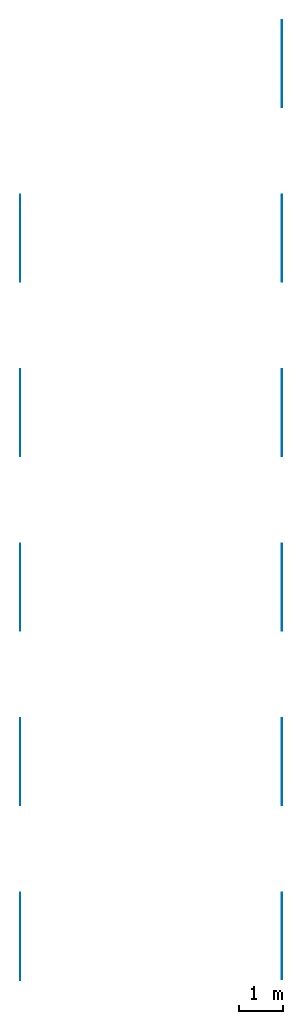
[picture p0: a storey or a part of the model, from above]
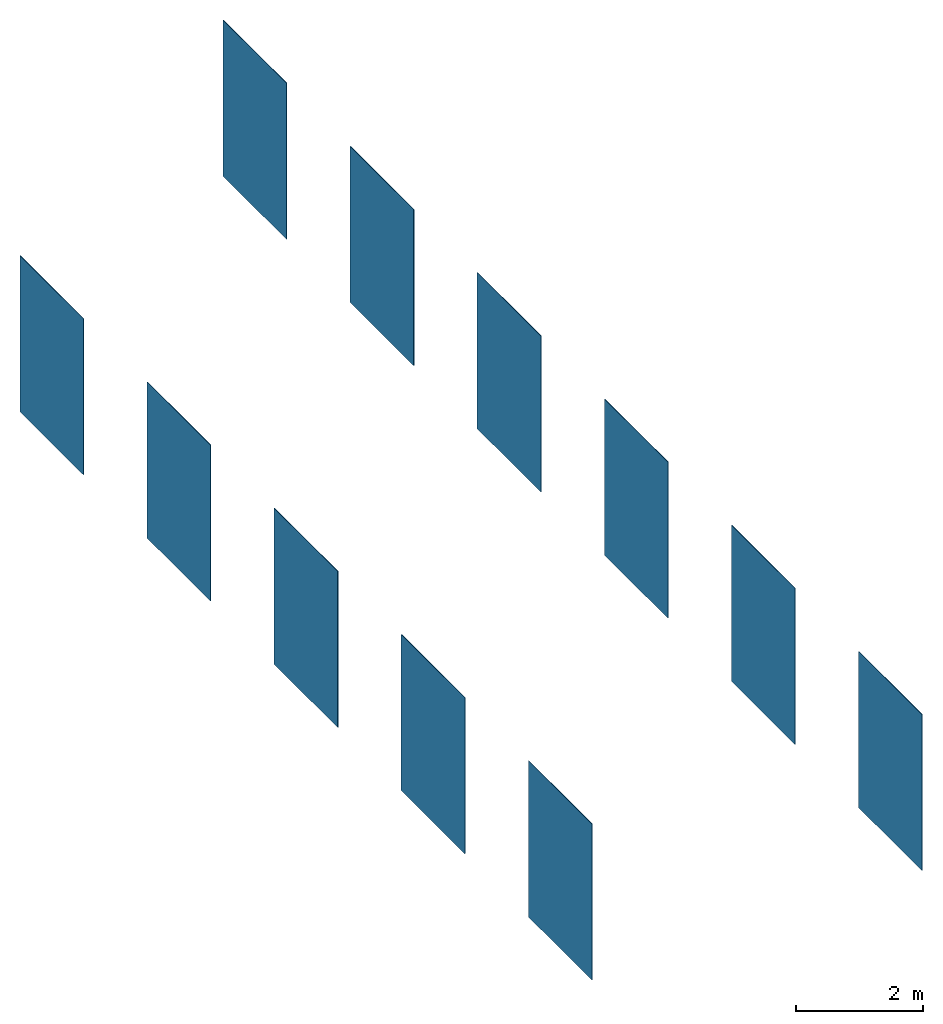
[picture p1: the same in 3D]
Properties of the parts of a building model (IFC2X3)

# File
Description: ViewDefinition [CoordinationView_V2.0]
File name: Project Number
Time: 2019-04-24T18:58:20
Written by: The EXPRESS Data Manager Version 5.02.0100.07 : 28 Aug 2013
Made in: 20181011_1645(x64) - Exporter 17.2.0.0 - Alternate UI 17.2.0.0
Comment: STEP Physical File produced by: The EXPRESS Data Manager Version 5.02.0100.07 : 28 Aug 2013 * Module: EDMstepFileFactory/EDMstandAlone * Creation date: Wed Apr 24 18:58:20 2019 * Host: aiepmoliner * Database: C:\Users\ES0050~1\AppData\Local\Temp\{C89440D0-0C4B-4D37-A4ED-84024C0F3F08}\ifc * Database version: 5507 * Database creation date: Wed Apr 24 18:58:17 2019 * Schema: IFC2X3 * Model: DataRepository.ifc * Model creation date: Wed Apr 24 18:58:18 2019 * Header model: DataRepository.ifc_HeaderModel * Header model creation date: Wed Apr 24 18:58:18 2019 * EDMuser: sdai-user * EDMgroup: sdai-group * License ID and type: 5605 : Permanent license. Expiry date: * EDMstepFileFactory options: 020000

# IfcProject, Project Number
LongName: Project Name; Phase: Project Status

# IfcSite, Default
RefLatitude: 42, 21, 31, 181945; RefLongitude: -71, -3, -24, -263305; RefElevation: 0 mm

# IfcBuildingStorey, Level 1
LongName: Level 1; Elevation: 0 mm

# IfcWallStandardCase: Basic Wall:PGR_AnticColonial_CeramicTiles_Nazari_Asilah-115x115mm-100213765, Basic Wall:PGR_AnticColonial_CeramicTiles_Nazari_Asilah-115x115mm-100213765:211309
In: Level 1
Type - PredefinedType: STANDARD; Material: PGR_AnticColonial_CeramicTiles_Nazari_Asilah-115x115mm-100213765 11 mm
Type - NBS_General - Author: Porcelanosa Group; BIMObjectName: PGR_AnticColonial_CeramicTiles_Nazari_Asilah-115x115mm-100213765; ManufacturerURL: anticcolonial.com; NBSDescription: Ceramic Tiles; NBSReference: 45-80-95/310; ProductInformation: http://calidad.info-grupo.com:8081/GeneraFicha3/PDF?articulo=100213765&lang=EN&un=0; Revision: n/a; Uniclass2015Code: Pr_35_93_96_19; Uniclass2015Title: Ceramic Tiles; Uniclass2015Version: Products v1.5; Version: 1
Type - COBie - AccessibilityPerformance: See ProductInformation (Technical PDF); AssetType: Fixed; Category: Pr_35_93_96_19:Ceramic Tiles; CodePerformance: ISO-13006:2012; UNE-EN 14411:2012; Color: n/a; Constituents: Clays, feldespat and glaze; Description: NAZARI series from ANTIC COLONIAL, 12.5x12.5 cm (11 mm thickness) and according to UNE-EN 14411; DurationUnit: year; ExpectedLife: 50; Features: See ProductInformation (Technical PDF); Grade: First quality; Manufacturer: bim.gp@porcelanosagrupo.com; ModelNumber: 100213765; ModelReference: Nazari Asilah 11.5x11.5x1-1.1 cm; Name: CeramicTiles_Nazari_Asilah-115x115mm-100213765; ReplacementCost: n/a; Shape: Squared; Size: 115x115x11 mm; Sustainability Performance: See ProductInformation (Technical PDF); WarrantyDescription: Manufacturer warranty, applicable worldwide, with the pertinent national legislation prevailing in all cases and covering at least a 3-year period; all products must have been manufactured and fitted in accordance with the Fabricator's Manual, and have been used and cared for in accordance with the Guide to Use, Cleaning and Care available on the web page www.porcelanosa.com; WarrantyDurationLabor: n/a; WarrantyDurationParts: 3; WarrantyDurationUnit: year; WarrantyGuarantorLabor: n/a; WarrantyGuarantorParts: bim.gp@porcelanosagrupo.com
Type - Pset_CoveringCommon - IsExternal: no; Reference: n/a; AcousticRating: n/a; Finish: Tone Variations, Gloss, Relief; FireRating: A1; FlammabilityRating: Class 0; FragilityRating: n/a; Material: Ceramic; SurfaceSpreadOfFlame: Class 0; ThermalTransmittance: 209.091 kg/K/s3; TotalThickness: 11 mm
Type - IFC - IfcExportAS: IfcCovering; IfcExportType: CLADDING
Type - NBS_Data - HasSurfaceRoughness: yes; AbrasionResistance: 1: Wall Tiles; BreakingStrength: n/a; ChemicalResistance: Class 'A' for swimming pools and cleaning products (resists attack); minimum Class 'B' for acids and bases; Collection: Ceramica Tradicional; CreationDate: 2019/04; Dcof: n/a; FlexuralStrength: n/a; FrostResistance: n/a; Group: N/A; MoistureExpansion: <0.1 mm/m; RampTest: n/a; RecycledContent: n/a; Series: Nazari; SlipResistanceValuePendulumTestValue: n/a; StainResistance: Class 5: Easy cleaning with water; SurfaceQuality: Without surface defects; ThermalShockResistance: Conforms to ISO 10545–12; UpecC: n/a; UpecE: n/a; UpecP: n/a; UpecU: n/a; WaterAbsorption: n/a
COBie - AssetIdentifier: n/a; BarCode: n/a; InstallationDate: 1900-12-31T23:59:59; TagNumber: n/a; WarrantyStartDate: 1900-12-31T23:59:59

# IfcWallStandardCase: Basic Wall:PGR_AnticColonial_CeramicTiles_Nazari_Casablanca_Brillo-115x115mm-100243592, Basic Wall:PGR_AnticColonial_CeramicTiles_Nazari_Casablanca_Brillo-115x115mm-100243592:211308
In: Level 1
Type - PredefinedType: STANDARD; Material: PGR_AnticColonial_CeramicTiles_Nazari_Casablanca_Brillo-115x115mm-100243592 11 mm
Type - NBS_General - Author: Porcelanosa Group; BIMObjectName: PGR_AnticColonial_CeramicTiles_Nazari_Casablanca_Brillo-115x115mm-100243592; ManufacturerURL: anticcolonial.com; NBSDescription: Ceramic Tiles; NBSReference: 45-80-95/310; ProductInformation: http://calidad.info-grupo.com:8081/GeneraFicha3/PDF?articulo=100243592&lang=EN&un=0; Revision: n/a; Uniclass2015Code: Pr_35_93_96_19; Uniclass2015Title: Ceramic Tiles; Uniclass2015Version: Products v1.5; Version: 1
Type - COBie - AccessibilityPerformance: See ProductInformation (Technical PDF); AssetType: Fixed; Category: Walls; CodePerformance: ISO-13006:2012; UNE-EN 14411:2012; Color: n/a; Constituents: Clays, feldespat and glaze; Description: NAZARI series from ANTIC COLONIAL, 11.5x11.5 cm (11 mm thickness) and according to UNE-EN 14411; DurationUnit: year; ExpectedLife: 50; Features: See ProductInformation (Technical PDF); Grade: First quality; Manufacturer: bim.gp@porcelanosagrupo.com; ModelNumber: 100243592; ModelReference: Nazari Casablanca Brillo 11.5x11.5x1-1.1 cm; Name: CeramicTiles_Nazari_Casablanca_Brillo-115x115mm-100243592; ReplacementCost: n/a; Shape: Squared; Size: 115x115x11 mm; Sustainability Performance: See ProductInformation (Technical PDF); WarrantyDescription: Manufacturer warranty, applicable worldwide, with the pertinent national legislation prevailing in all cases and covering at least a 3-year period; all products must have been manufactured and fitted in accordance with the Fabricator's Manual, and have been used and cared for in accordance with the Guide to Use, Cleaning and Care available on the web page www.porcelanosa.com; WarrantyDurationLabor: n/a; WarrantyDurationParts: 3; WarrantyDurationUnit: year; WarrantyGuarantorLabor: n/a; WarrantyGuarantorParts: bim.gp@porcelanosagrupo.com
Type - Pset_CoveringCommon - IsExternal: no; Reference: n/a; AcousticRating: n/a; Finish: Tone Variations, Gloss, Relief; FireRating: A1; FlammabilityRating: Class 0; FragilityRating: n/a; Material: Ceramic; SurfaceSpreadOfFlame: Class 0; ThermalTransmittance: 209.091 kg/K/s3; TotalThickness: 11 mm
Type - IFC - IfcExportAS: IfcCovering; IfcExportType: CLADDING
Type - NBS_Data - HasSurfaceRoughness: yes; AbrasionResistance: 1: Wall Tiles; BreakingStrength: n/a; ChemicalResistance: Class 'A' for swimming pools and cleaning products (resists attack); minimum Class 'B' for acids and bases; Collection: Ceramica Tradicional; CreationDate: 2019/04; Dcof: n/a; FlexuralStrength: n/a; FrostResistance: n/a; Group: N/A; MoistureExpansion: <0.1 mm/m; RampTest: n/a; RecycledContent: n/a; Series: Nazari; SlipResistanceValuePendulumTestValue: n/a; StainResistance: Class 5: Easy cleaning with water; SurfaceQuality: Without surface defects; ThermalShockResistance: Conforms to ISO 10545–12; UpecC: n/a; UpecE: n/a; UpecP: n/a; UpecU: n/a; WaterAbsorption: n/a
COBie - AssetIdentifier: n/a; BarCode: n/a; InstallationDate: 1900-12-31T23:59:59; TagNumber: n/a; WarrantyStartDate: 1900-12-31T23:59:59

# IfcWallStandardCase: Basic Wall:PGR_AnticColonial_CeramicTiles_Nazari_Casablanca_Mate-115x115mm-100243581, Basic Wall:PGR_AnticColonial_CeramicTiles_Nazari_Casablanca_Mate-115x115mm-100243581:211307
In: Level 1
Type - PredefinedType: STANDARD; Material: PGR_AnticColonial_CeramicTiles_Nazari_Casablanca_Mate-115x115mm-100243581 11 mm
Type - NBS_General - Author: Porcelanosa Group; BIMObjectName: PGR_AnticColonial_CeramicTiles_Nazari_Casablanca_Mate-115x115mm-100243581; ManufacturerURL: anticcolonial.com; NBSDescription: Ceramic Tiles; NBSReference: 45-80-95/310; ProductInformation: http://calidad.info-grupo.com:8081/GeneraFicha3/PDF?articulo=100243581&lang=EN&un=0; Revision: n/a; Uniclass2015Code: Pr_35_93_96_19; Uniclass2015Title: Ceramic Tiles; Uniclass2015Version: Products v1.5; Version: 1
Type - COBie - AccessibilityPerformance: See ProductInformation (Technical PDF); AssetType: Fixed; Category: Walls; CodePerformance: ISO-13006:2012; UNE-EN 14411:2012; Color: n/a; Constituents: Clays, feldespat and glaze; Description: NAZARI series from ANTIC COLONIAL, 11.5x11.5 cm (11 mm thickness) and according to UNE-EN 14411; DurationUnit: year; ExpectedLife: 50; Features: See ProductInformation (Technical PDF); Grade: First quality; Manufacturer: bim.gp@porcelanosagrupo.com; ModelNumber: 100243581; ModelReference: Nazari Casablanca Mate 11.5x11.5x1-1.1 cm; Name: CeramicTiles_Nazari_Casablanca_Mate-115x115mm-100243581; ReplacementCost: n/a; Shape: Squared; Size: 115x115x11 mm; Sustainability Performance: See ProductInformation (Technical PDF); WarrantyDescription: Manufacturer warranty, applicable worldwide, with the pertinent national legislation prevailing in all cases and covering at least a 3-year period; all products must have been manufactured and fitted in accordance with the Fabricator's Manual, and have been used and cared for in accordance with the Guide to Use, Cleaning and Care available on the web page www.porcelanosa.com; WarrantyDurationLabor: n/a; WarrantyDurationParts: 3; WarrantyDurationUnit: year; WarrantyGuarantorLabor: n/a; WarrantyGuarantorParts: bim.gp@porcelanosagrupo.com
Type - Pset_CoveringCommon - IsExternal: no; Reference: n/a; AcousticRating: n/a; Finish: Tone Variations, Matte, Relief; FireRating: A1; FlammabilityRating: Class 0; FragilityRating: n/a; Material: Ceramic; SurfaceSpreadOfFlame: Class 0; ThermalTransmittance: 209.091 kg/K/s3; TotalThickness: 11 mm
Type - IFC - IfcExportAS: IfcCovering; IfcExportType: CLADDING
Type - NBS_Data - HasSurfaceRoughness: yes; AbrasionResistance: 1: Wall Tiles; BreakingStrength: n/a; ChemicalResistance: Class 'A' for swimming pools and cleaning products (resists attack); minimum Class 'B' for acids and bases; Collection: Ceramica Tradicional; CreationDate: 2019/04; Dcof: n/a; FlexuralStrength: n/a; FrostResistance: n/a; Group: N/A; MoistureExpansion: <0.1 mm/m; RampTest: n/a; RecycledContent: n/a; Series: Nazari; SlipResistanceValuePendulumTestValue: n/a; StainResistance: Class 5: Easy cleaning with water; SurfaceQuality: Without surface defects; ThermalShockResistance: Conforms to ISO 10545–12; UpecC: n/a; UpecE: n/a; UpecP: n/a; UpecU: n/a; WaterAbsorption: n/a
COBie - AssetIdentifier: n/a; BarCode: n/a; InstallationDate: 1900-12-31T23:59:59; TagNumber: n/a; WarrantyStartDate: 1900-12-31T23:59:59

# IfcWallStandardCase: Basic Wall:PGR_AnticColonial_CeramicTiles_Nazari_Chauen-115x115mm-100213777, Basic Wall:PGR_AnticColonial_CeramicTiles_Nazari_Chauen-115x115mm-100213777:211306
In: Level 1
Type - PredefinedType: STANDARD; Material: PGR_AnticColonial_CeramicTiles_Nazari_Chauen-115x115mm-100213777 11 mm
Type - NBS_General - Author: Porcelanosa Group; BIMObjectName: PGR_AnticColonial_CeramicTiles_Nazari_Chauen-115x115mm-100213777; ManufacturerURL: anticcolonial.com; NBSDescription: Ceramic Tiles; NBSReference: 45-80-95/310; ProductInformation: http://calidad.info-grupo.com:8081/GeneraFicha3/PDF?articulo=100213777&lang=EN&un=0; Revision: n/a; Uniclass2015Code: Pr_35_93_96_19; Uniclass2015Title: Ceramic Tiles; Uniclass2015Version: Products v1.5; Version: 1
Type - COBie - AccessibilityPerformance: See ProductInformation (Technical PDF); AssetType: Fixed; Category: Pr_35_93_96_19:Ceramic Tiles; CodePerformance: ISO-13006:2012; UNE-EN 14411:2012; Color: n/a; Constituents: Clays, feldespat and glaze; Description: NAZARI series from ANTIC COLONIAL, 12.5x12.5 cm (11 mm thickness) and according to UNE-EN 14411; DurationUnit: year; ExpectedLife: 50; Features: See ProductInformation (Technical PDF); Grade: First quality; Manufacturer: bim.gp@porcelanosagrupo.com; ModelNumber: 100213777; ModelReference: Nazari Chauen 11.5x11.5x1-1.1 cm; Name: CeramicTiles_Nazari_Chauen-115x115mm-100213777; ReplacementCost: n/a; Shape: Squared; Size: 115x115x11 mm; Sustainability Performance: See ProductInformation (Technical PDF); WarrantyDescription: Manufacturer warranty, applicable worldwide, with the pertinent national legislation prevailing in all cases and covering at least a 3-year period; all products must have been manufactured and fitted in accordance with the Fabricator's Manual, and have been used and cared for in accordance with the Guide to Use, Cleaning and Care available on the web page www.porcelanosa.com; WarrantyDurationLabor: n/a; WarrantyDurationParts: 3; WarrantyDurationUnit: year; WarrantyGuarantorLabor: n/a; WarrantyGuarantorParts: bim.gp@porcelanosagrupo.com
Type - Pset_CoveringCommon - IsExternal: no; Reference: n/a; AcousticRating: n/a; Finish: Tone Variations, Gloss, Relief; FireRating: A1; FlammabilityRating: Class 0; FragilityRating: n/a; Material: Ceramic; SurfaceSpreadOfFlame: Class 0; ThermalTransmittance: 209.091 kg/K/s3; TotalThickness: 11 mm
Type - IFC - IfcExportAS: IfcCovering; IfcExportType: CLADDING
Type - NBS_Data - HasSurfaceRoughness: yes; AbrasionResistance: 1: Wall Tiles; BreakingStrength: n/a; ChemicalResistance: Class 'A' for swimming pools and cleaning products (resists attack); minimum Class 'B' for acids and bases; Collection: Ceramica Tradicional; CreationDate: 2019/04; Dcof: n/a; FlexuralStrength: n/a; FrostResistance: n/a; Group: N/A; MoistureExpansion: <0.1 mm/m; RampTest: n/a; RecycledContent: n/a; Series: Nazari; SlipResistanceValuePendulumTestValue: n/a; StainResistance: Class 5: Easy cleaning with water; SurfaceQuality: Without surface defects; ThermalShockResistance: Conforms to ISO 10545–12; UpecC: n/a; UpecE: n/a; UpecP: n/a; UpecU: n/a; WaterAbsorption: n/a
COBie - AssetIdentifier: n/a; BarCode: n/a; InstallationDate: 1900-12-31T23:59:59; TagNumber: n/a; WarrantyStartDate: 1900-12-31T23:59:59

# IfcWallStandardCase: Basic Wall:PGR_AnticColonial_CeramicTiles_Nazari_Fes-115x115mm-100213766, Basic Wall:PGR_AnticColonial_CeramicTiles_Nazari_Fes-115x115mm-100213766:211305
In: Level 1
Type - PredefinedType: STANDARD; Material: PGR_AnticColonial_CeramicTiles_Nazari_Fes-115x115mm-100213766 11 mm
Type - NBS_General - Author: Porcelanosa Group; BIMObjectName: PGR_AnticColonial_CeramicTiles_Nazari_Fes-115x115mm-100213766; ManufacturerURL: anticcolonial.com; NBSDescription: Ceramic Tiles; NBSReference: 45-80-95/310; ProductInformation: http://calidad.info-grupo.com:8081/GeneraFicha3/PDF?articulo=100213766&lang=EN&un=0; Revision: n/a; Uniclass2015Code: Pr_35_93_96_19; Uniclass2015Title: Ceramic Tiles; Uniclass2015Version: Products v1.5; Version: 1
Type - COBie - AccessibilityPerformance: See ProductInformation (Technical PDF); AssetType: Fixed; Category: Walls; CodePerformance: ISO-13006:2012; UNE-EN 14411:2012; Color: n/a; Constituents: Clays, feldespat and glaze; Description: NAZARI series from ANTIC COLONIAL, 12.5x12.5 cm (11 mm thickness) and according to UNE-EN 14411; DurationUnit: year; ExpectedLife: 50; Features: See ProductInformation (Technical PDF); Grade: First quality; Manufacturer: bim.gp@porcelanosagrupo.com; ModelNumber: 100213766; ModelReference: Nazari Fes 11.5x11.5x1-1.1 cm; Name: CeramicTiles_Nazari_Fes-115x115mm-100213766; ReplacementCost: n/a; Shape: Squared; Size: 115x115x11 mm; Sustainability Performance: See ProductInformation (Technical PDF); WarrantyDescription: Manufacturer warranty, applicable worldwide, with the pertinent national legislation prevailing in all cases and covering at least a 3-year period; all products must have been manufactured and fitted in accordance with the Fabricator's Manual, and have been used and cared for in accordance with the Guide to Use, Cleaning and Care available on the web page www.porcelanosa.com; WarrantyDurationLabor: n/a; WarrantyDurationParts: 3; WarrantyDurationUnit: year; WarrantyGuarantorLabor: n/a; WarrantyGuarantorParts: bim.gp@porcelanosagrupo.com
Type - Pset_CoveringCommon - IsExternal: no; Reference: n/a; AcousticRating: n/a; Finish: Tone Variations, Gloss, Relief; FireRating: A1; FlammabilityRating: Class 0; FragilityRating: n/a; Material: Ceramic; SurfaceSpreadOfFlame: Class 0; ThermalTransmittance: 209.091 kg/K/s3; TotalThickness: 11 mm
Type - IFC - IfcExportAS: IfcCovering; IfcExportType: CLADDING
Type - NBS_Data - HasSurfaceRoughness: yes; AbrasionResistance: 1: Wall Tiles; BreakingStrength: n/a; ChemicalResistance: Class 'A' for swimming pools and cleaning products (resists attack); minimum Class 'B' for acids and bases; Collection: Ceramica Tradicional; CreationDate: 2019/04; Dcof: n/a; FlexuralStrength: n/a; FrostResistance: n/a; Group: N/A; MoistureExpansion: <0.1 mm/m; RampTest: n/a; RecycledContent: n/a; Series: Nazari; SlipResistanceValuePendulumTestValue: n/a; StainResistance: Class 5: Easy cleaning with water; SurfaceQuality: Without surface defects; ThermalShockResistance: Conforms to ISO 10545–12; UpecC: n/a; UpecE: n/a; UpecP: n/a; UpecU: n/a; WaterAbsorption: n/a
COBie - AssetIdentifier: n/a; BarCode: n/a; InstallationDate: 1900-12-31T23:59:59; TagNumber: n/a; WarrantyStartDate: 1900-12-31T23:59:59

# IfcWallStandardCase: Basic Wall:PGR_AnticColonial_CeramicTiles_Nazari_Ifrane-115x115mm-100213784, Basic Wall:PGR_AnticColonial_CeramicTiles_Nazari_Ifrane-115x115mm-100213784:211304
In: Level 1
Type - PredefinedType: STANDARD; Material: PGR_AnticColonial_CeramicTiles_Nazari_Ifrane-115x115mm-100213784 11 mm
Type - NBS_General - Author: Porcelanosa Group; BIMObjectName: PGR_AnticColonial_CeramicTiles_Nazari_Ifrane-115x115mm-100213784; ManufacturerURL: anticcolonial.com; NBSDescription: Ceramic Tiles; NBSReference: 45-80-95/310; ProductInformation: http://calidad.info-grupo.com:8081/GeneraFicha3/PDF?articulo=100213784&lang=EN&un=0; Revision: n/a; Uniclass2015Code: Pr_35_93_96_19; Uniclass2015Title: Ceramic Tiles; Uniclass2015Version: Products v1.5; Version: 1
Type - COBie - AccessibilityPerformance: See ProductInformation (Technical PDF); AssetType: Fixed; Category: Pr_35_93_96_19:Ceramic Tiles; CodePerformance: ISO-13006:2012; UNE-EN 14411:2012; Color: n/a; Constituents: Clays, feldespat and glaze; Description: NAZARI series from ANTIC COLONIAL, 12.5x12.5 cm (11 mm thickness) and according to UNE-EN 14411; DurationUnit: year; ExpectedLife: 50; Features: See ProductInformation (Technical PDF); Grade: First quality; Manufacturer: bim.gp@porcelanosagrupo.com; ModelNumber: 100213784; ModelReference: Nazari Ifrane 11.5x11.5x1-1.1 cm; Name: CeramicTiles_Nazari_Ifrane-115x115mm-100213784; ReplacementCost: n/a; Shape: Squared; Size: 115x115x11 mm; Sustainability Performance: See ProductInformation (Technical PDF); WarrantyDescription: Manufacturer warranty, applicable worldwide, with the pertinent national legislation prevailing in all cases and covering at least a 3-year period; all products must have been manufactured and fitted in accordance with the Fabricator's Manual, and have been used and cared for in accordance with the Guide to Use, Cleaning and Care available on the web page www.porcelanosa.com; WarrantyDurationLabor: n/a; WarrantyDurationParts: 3; WarrantyDurationUnit: year; WarrantyGuarantorLabor: n/a; WarrantyGuarantorParts: bim.gp@porcelanosagrupo.com
Type - Pset_CoveringCommon - AcousticRating: n/a; Finish: Tone Variations, Gloss, Relief; FireRating: A1; FlammabilityRating: Class 0; FragilityRating: n/a; IsExternal: no; Material: Ceramic; SurfaceSpreadOfFlame: Class 0; ThermalTransmittance: 209.091 kg/K/s3; TotalThickness: 11 mm; Reference: n/a
Type - IFC - IfcExportAS: IfcCovering; IfcExportType: CLADDING
Type - NBS_Data - AbrasionResistance: 1: Wall Tiles; BreakingStrength: n/a; ChemicalResistance: Class 'A' for swimming pools and cleaning products (resists attack); minimum Class 'B' for acids and bases; Collection: Ceramica Tradicional; CreationDate: 2019/04; Dcof: n/a; FlexuralStrength: n/a; FrostResistance: n/a; Group: N/A; HasSurfaceRoughness: yes; MoistureExpansion: <0.1 mm/m; RampTest: n/a; RecycledContent: n/a; Series: Nazari; SlipResistanceValuePendulumTestValue: n/a; StainResistance: Class 5: Easy cleaning with water; SurfaceQuality: Without surface defects; ThermalShockResistance: Conforms to ISO 10545–12; UpecC: n/a; UpecE: n/a; UpecP: n/a; UpecU: n/a; WaterAbsorption: n/a
COBie - AssetIdentifier: n/a; BarCode: n/a; InstallationDate: 1900-12-31T23:59:59; TagNumber: n/a; WarrantyStartDate: 1900-12-31T23:59:59

# IfcWallStandardCase: Basic Wall:PGR_AnticColonial_CeramicTiles_Nazari_Marrakech-115x115mm-100213785, Basic Wall:PGR_AnticColonial_CeramicTiles_Nazari_Marrakech-115x115mm-100213785:213014
In: Level 1
Type - PredefinedType: STANDARD; Material: PGR_AnticColonial_CeramicTiles_Nazari_Marrakech-115x115mm-100213785 11 mm
Type - NBS_General - Author: Porcelanosa Group; BIMObjectName: PGR_AnticColonial_CeramicTiles_Nazari_Marrakech-115x115mm-100213785; ManufacturerURL: anticcolonial.com; NBSDescription: Ceramic Tiles; NBSReference: 45-80-95/310; ProductInformation: http://calidad.info-grupo.com:8081/GeneraFicha3/PDF?articulo=100213785&lang=EN&un=0; Revision: n/a; Uniclass2015Code: Pr_35_93_96_19; Uniclass2015Title: Ceramic Tiles; Uniclass2015Version: Products v1.5; Version: 1
Type - COBie - AccessibilityPerformance: See ProductInformation (Technical PDF); AssetType: Fixed; Category: Pr_35_93_96_19:Ceramic Tiles; CodePerformance: ISO-13006:2012; UNE-EN 14411:2012; Color: n/a; Constituents: Clays, feldespat and glaze; Description: NAZARI series from ANTIC COLONIAL, 12.5x12.5 cm (11 mm thickness) and according to UNE-EN 14411; DurationUnit: year; ExpectedLife: 50; Features: See ProductInformation (Technical PDF); Grade: First quality; Manufacturer: bim.gp@porcelanosagrupo.com; ModelNumber: 100213785; ModelReference: Nazari Marrakech 11.5x11.5x1-1.1 cm; Name: CeramicTiles_Nazari_Marrakech-115x115mm-100213785; ReplacementCost: n/a; Shape: Squared; Size: 115x115x11 mm; Sustainability Performance: See ProductInformation (Technical PDF); WarrantyDescription: Manufacturer warranty, applicable worldwide, with the pertinent national legislation prevailing in all cases and covering at least a 3-year period; all products must have been manufactured and fitted in accordance with the Fabricator's Manual, and have been used and cared for in accordance with the Guide to Use, Cleaning and Care available on the web page www.porcelanosa.com; WarrantyDurationLabor: n/a; WarrantyDurationParts: 3; WarrantyDurationUnit: year; WarrantyGuarantorLabor: n/a; WarrantyGuarantorParts: bim.gp@porcelanosagrupo.com
Type - Pset_CoveringCommon - IsExternal: no; Reference: n/a; AcousticRating: n/a; Finish: Tone Variations, Gloss, Relief; FireRating: A1; FlammabilityRating: Class 0; FragilityRating: n/a; Material: Ceramic; SurfaceSpreadOfFlame: Class 0; ThermalTransmittance: 209.091 kg/K/s3; TotalThickness: 11 mm
Type - IFC - IfcExportAS: IfcCovering; IfcExportType: CLADDING
Type - NBS_Data - HasSurfaceRoughness: yes; AbrasionResistance: 1: Wall Tiles; BreakingStrength: n/a; ChemicalResistance: Class 'A' for swimming pools and cleaning products (resists attack); minimum Class 'B' for acids and bases; Collection: Ceramica Tradicional; CreationDate: 2019/04; Dcof: n/a; FlexuralStrength: n/a; FrostResistance: n/a; Group: N/A; MoistureExpansion: <0.1 mm/m; RampTest: n/a; RecycledContent: n/a; Series: Nazari; SlipResistanceValuePendulumTestValue: n/a; StainResistance: Class 5: Easy cleaning with water; SurfaceQuality: Without surface defects; ThermalShockResistance: Conforms to ISO 10545–12; UpecC: n/a; UpecE: n/a; UpecP: n/a; UpecU: n/a; WaterAbsorption: n/a
COBie - AssetIdentifier: n/a; BarCode: n/a; InstallationDate: 1900-12-31T23:59:59; TagNumber: n/a; WarrantyStartDate: 1900-12-31T23:59:59

# IfcWallStandardCase: Basic Wall:PGR_AnticColonial_CeramicTiles_Nazari_Rabat-115x115mm-100243567, Basic Wall:PGR_AnticColonial_CeramicTiles_Nazari_Rabat-115x115mm-100243567:213013
In: Level 1
Type - PredefinedType: STANDARD; Material: PGR_AnticColonial_CeramicTiles_Nazari_Rabat-115x115mm-100243567 11 mm
Type - NBS_General - Author: Porcelanosa Group; BIMObjectName: PGR_AnticColonial_CeramicTiles_Nazari_Rabat-115x115mm-100243567; ManufacturerURL: anticcolonial.com; NBSDescription: Ceramic Tiles; NBSReference: 45-80-95/310; ProductInformation: http://calidad.info-grupo.com:8081/GeneraFicha3/PDF?articulo=100243567&lang=EN&un=0; Revision: n/a; Uniclass2015Code: Pr_35_93_96_19; Uniclass2015Title: Ceramic Tiles; Uniclass2015Version: Products v1.5; Version: 1
Type - COBie - AccessibilityPerformance: See ProductInformation (Technical PDF); AssetType: Fixed; Category: Pr_35_93_96_19:Ceramic Tiles; CodePerformance: ISO-13006:2012; UNE-EN 14411:2012; Color: n/a; Constituents: Clays, feldespat and glaze; Description: NAZARI series from ANTIC COLONIAL, 11.5x11.5 cm (11 mm thickness) and according to UNE-EN 14411; DurationUnit: year; ExpectedLife: 50; Features: See ProductInformation (Technical PDF); Grade: First quality; Manufacturer: bim.gp@porcelanosagrupo.com; ModelNumber: 100243567; ModelReference: Nazari Rabat 11.5x11.5x1-1.1 cm; Name: CeramicTiles_Nazari_Rabat-115x115mm-100243567; ReplacementCost: n/a; Shape: Squared; Size: 115x115x11 mm; Sustainability Performance: See ProductInformation (Technical PDF); WarrantyDescription: Manufacturer warranty, applicable worldwide, with the pertinent national legislation prevailing in all cases and covering at least a 3-year period; all products must have been manufactured and fitted in accordance with the Fabricator's Manual, and have been used and cared for in accordance with the Guide to Use, Cleaning and Care available on the web page www.porcelanosa.com; WarrantyDurationLabor: n/a; WarrantyDurationParts: 3; WarrantyDurationUnit: year; WarrantyGuarantorLabor: n/a; WarrantyGuarantorParts: bim.gp@porcelanosagrupo.com
Type - Pset_CoveringCommon - IsExternal: no; Reference: n/a; AcousticRating: n/a; Finish: Tone Variations, Gloss, Relief; FireRating: A1; FlammabilityRating: Class 0; FragilityRating: n/a; Material: Ceramic; SurfaceSpreadOfFlame: Class 0; ThermalTransmittance: 209.091 kg/K/s3; TotalThickness: 11 mm
Type - IFC - IfcExportAS: IfcCovering; IfcExportType: CLADDING
Type - NBS_Data - HasSurfaceRoughness: yes; AbrasionResistance: 1: Wall Tiles; BreakingStrength: n/a; ChemicalResistance: Class 'A' for swimming pools and cleaning products (resists attack); minimum Class 'B' for acids and bases; Collection: Ceramica Tradicional; CreationDate: 2019/04; Dcof: n/a; FlexuralStrength: n/a; FrostResistance: n/a; Group: N/A; MoistureExpansion: <0.1 mm/m; RampTest: n/a; RecycledContent: n/a; Series: Nazari; SlipResistanceValuePendulumTestValue: n/a; StainResistance: Class 5: Easy cleaning with water; SurfaceQuality: Without surface defects; ThermalShockResistance: Conforms to ISO 10545–12; UpecC: n/a; UpecE: n/a; UpecP: n/a; UpecU: n/a; WaterAbsorption: n/a
COBie - AssetIdentifier: n/a; BarCode: n/a; InstallationDate: 1900-12-31T23:59:59; TagNumber: n/a; WarrantyStartDate: 1900-12-31T23:59:59

# IfcWallStandardCase: Basic Wall:PGR_AnticColonial_CeramicTiles_Nazari_Safi-115x115mm-100223245, Basic Wall:PGR_AnticColonial_CeramicTiles_Nazari_Safi-115x115mm-100223245:213012
In: Level 1
Type - PredefinedType: STANDARD; Material: PGR_AnticColonial_CeramicTiles_Nazari_Safi-115x115mm-100223245 11 mm
Type - NBS_General - Author: Porcelanosa Group; BIMObjectName: PGR_AnticColonial_CeramicTiles_Nazari_Safi-115x115mm-100223245; ManufacturerURL: anticcolonial.com; NBSDescription: Ceramic Tiles; NBSReference: 45-80-95/310; ProductInformation: http://calidad.info-grupo.com:8081/GeneraFicha3/PDF?articulo=100223245&lang=EN&un=0; Revision: n/a; Uniclass2015Code: Pr_35_93_96_19; Uniclass2015Title: Ceramic Tiles; Uniclass2015Version: Products v1.5; Version: 1
Type - COBie - AccessibilityPerformance: See ProductInformation (Technical PDF); AssetType: Fixed; Category: Walls; CodePerformance: ISO-13006:2012; UNE-EN 14411:2012; Color: n/a; Constituents: Clays, feldespat and glaze; Description: NAZARI series from ANTIC COLONIAL, 11.5x11.5 cm (11 mm thickness) and according to UNE-EN 14411; DurationUnit: year; ExpectedLife: 50; Features: See ProductInformation (Technical PDF); Grade: First quality; Manufacturer: bim.gp@porcelanosagrupo.com; ModelNumber: 100223245; ModelReference: Nazari Safi 11.5x11.5x1-1.1 cm; Name: CeramicTiles_Nazari_Safi-115x115mm-100223245; ReplacementCost: n/a; Shape: Squared; Size: 115x115x11 mm; Sustainability Performance: See ProductInformation (Technical PDF); WarrantyDescription: Manufacturer warranty, applicable worldwide, with the pertinent national legislation prevailing in all cases and covering at least a 3-year period; all products must have been manufactured and fitted in accordance with the Fabricator's Manual, and have been used and cared for in accordance with the Guide to Use, Cleaning and Care available on the web page www.porcelanosa.com; WarrantyDurationLabor: n/a; WarrantyDurationParts: 3; WarrantyDurationUnit: year; WarrantyGuarantorLabor: n/a; WarrantyGuarantorParts: bim.gp@porcelanosagrupo.com
Type - Pset_CoveringCommon - IsExternal: no; Reference: n/a; AcousticRating: n/a; Finish: Tone Variations, Gloss, Relief; FireRating: A1; FlammabilityRating: Class 0; FragilityRating: n/a; Material: Ceramic; SurfaceSpreadOfFlame: Class 0; ThermalTransmittance: 209.091 kg/K/s3; TotalThickness: 11 mm
Type - IFC - IfcExportAS: IfcCovering; IfcExportType: CLADDING
Type - NBS_Data - HasSurfaceRoughness: yes; AbrasionResistance: 1: Wall Tiles; BreakingStrength: n/a; ChemicalResistance: Class 'A' for swimming pools and cleaning products (resists attack); minimum Class 'B' for acids and bases; Collection: Ceramica Tradicional; CreationDate: 2019/04; Dcof: n/a; FlexuralStrength: n/a; FrostResistance: n/a; Group: N/A; MoistureExpansion: <0.1 mm/m; RampTest: n/a; RecycledContent: n/a; Series: Nazari; SlipResistanceValuePendulumTestValue: n/a; StainResistance: Class 5: Easy cleaning with water; SurfaceQuality: Without surface defects; ThermalShockResistance: Conforms to ISO 10545–12; UpecC: n/a; UpecE: n/a; UpecP: n/a; UpecU: n/a; WaterAbsorption: n/a
COBie - AssetIdentifier: n/a; BarCode: n/a; InstallationDate: 1900-12-31T23:59:59; TagNumber: n/a; WarrantyStartDate: 1900-12-31T23:59:59

# IfcWallStandardCase: Basic Wall:PGR_AnticColonial_CeramicTiles_Nazari_Sale-115x115mm-100220354, Basic Wall:PGR_AnticColonial_CeramicTiles_Nazari_Sale-115x115mm-100220354:213011
In: Level 1
Type - PredefinedType: STANDARD; Material: PGR_AnticColonial_CeramicTiles_Nazari_Sale-115x115mm-100220354 11 mm
Type - NBS_General - Author: Porcelanosa Group; BIMObjectName: PGR_AnticColonial_CeramicTiles_Nazari_Sale-115x115mm-100220354; ManufacturerURL: anticcolonial.com; NBSDescription: Ceramic Tiles; NBSReference: 45-80-95/310; ProductInformation: http://calidad.info-grupo.com:8081/GeneraFicha3/PDF?articulo=100220354&lang=EN&un=0; Revision: n/a; Uniclass2015Code: Pr_35_93_96_19; Uniclass2015Title: Ceramic Tiles; Uniclass2015Version: Products v1.5; Version: 1
Type - COBie - AccessibilityPerformance: See ProductInformation (Technical PDF); AssetType: Fixed; Category: Pr_35_93_96_19:Ceramic Tiles; CodePerformance: ISO-13006:2012; UNE-EN 14411:2012; Color: n/a; Constituents: Clays, feldespat and glaze; Description: NAZARI series from ANTIC COLONIAL, 11.5x11.5 cm (11 mm thickness) and according to UNE-EN 14411; DurationUnit: year; ExpectedLife: 50; Features: See ProductInformation (Technical PDF); Grade: First quality; Manufacturer: bim.gp@porcelanosagrupo.com; ModelNumber: 100220354; ModelReference: Nazari Sale 11.5x11.5x1-1.1 cm; Name: CeramicTiles_Nazari_Sale-115x115mm-100220354; ReplacementCost: n/a; Shape: Squared; Size: 115x115x11 mm; Sustainability Performance: See ProductInformation (Technical PDF); WarrantyDescription: Manufacturer warranty, applicable worldwide, with the pertinent national legislation prevailing in all cases and covering at least a 3-year period; all products must have been manufactured and fitted in accordance with the Fabricator's Manual, and have been used and cared for in accordance with the Guide to Use, Cleaning and Care available on the web page www.porcelanosa.com; WarrantyDurationLabor: n/a; WarrantyDurationParts: 3; WarrantyDurationUnit: year; WarrantyGuarantorLabor: n/a; WarrantyGuarantorParts: bim.gp@porcelanosagrupo.com
Type - Pset_CoveringCommon - IsExternal: no; Reference: n/a; AcousticRating: n/a; Finish: Tone Variations, Gloss, Relief; FireRating: A1; FlammabilityRating: Class 0; FragilityRating: n/a; Material: Ceramic; SurfaceSpreadOfFlame: Class 0; ThermalTransmittance: 209.091 kg/K/s3; TotalThickness: 11 mm
Type - IFC - IfcExportAS: IfcCovering; IfcExportType: CLADDING
Type - NBS_Data - HasSurfaceRoughness: yes; AbrasionResistance: 1: Wall Tiles; BreakingStrength: n/a; ChemicalResistance: Class 'A' for swimming pools and cleaning products (resists attack); minimum Class 'B' for acids and bases; Collection: Ceramica Tradicional; CreationDate: 2019/04; Dcof: n/a; FlexuralStrength: n/a; FrostResistance: n/a; Group: N/A; MoistureExpansion: <0.1 mm/m; RampTest: n/a; RecycledContent: n/a; Series: Nazari; SlipResistanceValuePendulumTestValue: n/a; StainResistance: Class 5: Easy cleaning with water; SurfaceQuality: Without surface defects; ThermalShockResistance: Conforms to ISO 10545–12; UpecC: n/a; UpecE: n/a; UpecP: n/a; UpecU: n/a; WaterAbsorption: n/a
COBie - AssetIdentifier: n/a; BarCode: n/a; InstallationDate: 1900-12-31T23:59:59; TagNumber: n/a; WarrantyStartDate: 1900-12-31T23:59:59

# IfcWallStandardCase: Basic Wall:PGR_AnticColonial_CeramicTiles_Nazari_Yadida-115x115mm-100243601, Basic Wall:PGR_AnticColonial_CeramicTiles_Nazari_Yadida-115x115mm-100243601:213010
In: Level 1
Type - PredefinedType: STANDARD; Material: PGR_AnticColonial_CeramicTiles_Nazari_Yadida-115x115mm-100243601 11 mm
Type - NBS_General - Author: Porcelanosa Group; BIMObjectName: PGR_AnticColonial_CeramicTiles_Nazari_Yadida-115x115mm-100243601; ManufacturerURL: anticcolonial.com; NBSDescription: Ceramic Tiles; NBSReference: 45-80-95/310; ProductInformation: http://calidad.info-grupo.com:8081/GeneraFicha3/PDF?articulo=100243601&lang=EN&un=0; Revision: n/a; Uniclass2015Code: Pr_35_93_96_19; Uniclass2015Title: Ceramic Tiles; Uniclass2015Version: Products v1.5; Version: 1
Type - COBie - AccessibilityPerformance: See ProductInformation (Technical PDF); AssetType: Fixed; Category: Walls; CodePerformance: ISO-13006:2012; UNE-EN 14411:2012; Color: n/a; Constituents: Clays, feldespat and glaze; Description: NAZARI series from ANTIC COLONIAL, 11.5x11.5 cm (11 mm thickness) and according to UNE-EN 14411; DurationUnit: year; ExpectedLife: 50; Features: See ProductInformation (Technical PDF); Grade: First quality; Manufacturer: bim.gp@porcelanosagrupo.com; ModelNumber: 100243601; ModelReference: Nazari Yadida 11.5x11.5x1-1.1 cm; Name: CeramicTiles_Nazari_Yadida-115x115mm-100243601; ReplacementCost: n/a; Shape: Squared; Size: 115x115x11 mm; Sustainability Performance: See ProductInformation (Technical PDF); WarrantyDescription: Manufacturer warranty, applicable worldwide, with the pertinent national legislation prevailing in all cases and covering at least a 3-year period; all products must have been manufactured and fitted in accordance with the Fabricator's Manual, and have been used and cared for in accordance with the Guide to Use, Cleaning and Care available on the web page www.porcelanosa.com; WarrantyDurationLabor: n/a; WarrantyDurationParts: 3; WarrantyDurationUnit: year; WarrantyGuarantorLabor: n/a; WarrantyGuarantorParts: bim.gp@porcelanosagrupo.com
Type - Pset_CoveringCommon - IsExternal: no; Reference: n/a; AcousticRating: n/a; Finish: Tone Variations, Gloss, Relief; FireRating: A1; FlammabilityRating: Class 0; FragilityRating: n/a; Material: Ceramic; SurfaceSpreadOfFlame: Class 0; ThermalTransmittance: 209.091 kg/K/s3; TotalThickness: 11 mm
Type - IFC - IfcExportAS: IfcCovering; IfcExportType: CLADDING
Type - NBS_Data - HasSurfaceRoughness: yes; AbrasionResistance: 1: Wall Tiles; BreakingStrength: n/a; ChemicalResistance: Class 'A' for swimming pools and cleaning products (resists attack); minimum Class 'B' for acids and bases; Collection: Ceramica Tradicional; CreationDate: 2019/04; Dcof: n/a; FlexuralStrength: n/a; FrostResistance: n/a; Group: N/A; MoistureExpansion: <0.1 mm/m; RampTest: n/a; RecycledContent: n/a; Series: Nazari; SlipResistanceValuePendulumTestValue: n/a; StainResistance: Class 5: Easy cleaning with water; SurfaceQuality: Without surface defects; ThermalShockResistance: Conforms to ISO 10545–12; UpecC: n/a; UpecE: n/a; UpecP: n/a; UpecU: n/a; WaterAbsorption: n/a
COBie - AssetIdentifier: n/a; BarCode: n/a; InstallationDate: 1900-12-31T23:59:59; TagNumber: n/a; WarrantyStartDate: 1900-12-31T23:59:59
